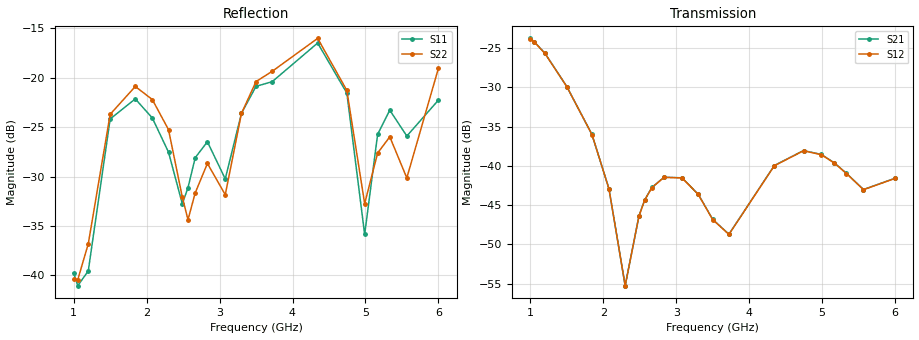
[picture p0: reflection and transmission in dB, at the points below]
!Agilent Technologies,E8364B,MY43040528,A.07.50.67
!Agilent E8364B: A.07.50.67
!Date: Sunday, March 01, 2026 20:36:29
!Correction: S11(Full 2 Port(1,2))
!S21(Full 2 Port(1,2))
!S12(Full 2 Port(1,2))
!S22(Full 2 Port(1,2))
!S2P File: Measurements: S11, S21, S12, S22:
# Hz S  dB  R 50
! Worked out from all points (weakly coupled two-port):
!   451 points, 1 GHz to 6 GHz, reference 50 ohm
!   highest |S21| = -23.74 dB at 1 GHz (marker M1); lowest = -55.3 dB at 2.3 GHz (marker M2)
!   lowest |S11| = -41.0 dB at 1.056 GHz (marker M3), VSWR 1.02, Z = 49.8 + j0.852 ohm
!   |S11| at or under -10 dB: start of sweep to end of sweep
!   |S22| runs from -40.9 to -15.7 dB; largest |S21 - S12| = 0.00017
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1e9  -39.77 78.1  -23.74 148.8  -23.76 148.7  -40.36 34.4
1.055556e9  -41.04 105.3  -24.20 116.6  -24.22 116.6  -40.45 58.0
1.2e9  -39.55 153.2  -25.63 33.3  -25.66 33.2  -36.80 85.7
1.5e9  -24.16 153.3  -29.89 -135.2  -29.90 -135.3  -23.69 75.4
1.844444e9  -22.13 92.7  -35.99 38.4  -36.00 38.5  -20.87 -1.8
2.077778e9  -24.06 65.3  -42.91 -84.5  -42.93 -84.5  -22.19 -44.7
2.3e9  -27.52 46.1  -55.27 -131.3  -55.27 -131.6  -25.24 -84.2
2.488889e9  -32.75 65.5  -46.37 -171.6  -46.41 -171.6  -32.06 -100.9
2.566667e9  -31.12 84.4  -44.35 149.3  -44.37 149.3  -34.37 -81.5
2.666667e9  -28.07 84.5  -42.74 96.5  -42.76 96.5  -31.63 -61.4
2.833333e9  -26.47 63.8  -41.44 6.7  -41.46 6.7  -28.66 -83.0
3.077778e9  -30.23 69.6  -41.52 -126.2  -41.53 -126.2  -31.83 -79.6
3.3e9  -23.58 81.1  -43.59 116.5  -43.61 116.6  -23.60 -82.0
3.5e9  -20.86 54.6  -46.82 23.2  -46.85 23.2  -20.37 -119.9
3.722222e9  -20.38 35.6  -48.71 -52.3  -48.73 -52.3  -19.33 -152.6
4.344444e9  -16.47 -38.8  -39.95 13.3  -39.98 13.4  -16.00 100.5
4.744444e9  -21.54 -103.4  -38.04 146.3  -38.07 146.3  -21.27 18.7
4.988889e9  -35.85 -76.8  -38.54 1.4  -38.57 1.4  -32.73 14.8
5.166667e9  -25.71 -41.0  -39.61 -106.1  -39.63 -106.1  -27.61 47.6
5.333333e9  -23.27 -67.2  -40.95 149.4  -40.97 149.4  -25.97 19.0
5.566667e9  -25.89 -86.3  -43.01 -8.8  -43.03 -8.8  -30.13 22.9
6e9  -22.25 -82.8  -41.57 42.4  -41.59 42.4  -19.03 -17.4
